! (c) 2009  Infineon Technologies AG, Munich
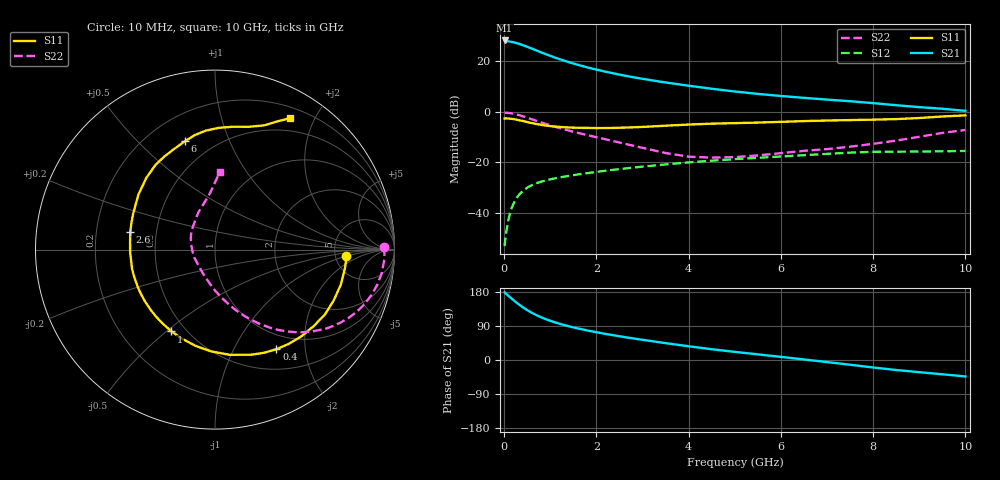
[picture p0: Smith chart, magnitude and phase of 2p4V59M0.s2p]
! Infineon Technologies  Discrete & RF Semiconductors
! BFP420
! VCE =  4.5 V,  IC =  9.0 mA
! Common Emitter S-Parameters:  Nov 2009
# GHz  S  MA  R  50
!  f  S11  S21  S12  S22
! GHz  MAG  ANG  MAG  ANG  MAG  ANG  MAG  ANG
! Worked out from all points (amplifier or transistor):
!   46 points, 10 MHz to 10 GHz, reference 50 ohm
!   highest |S21| = 28.1 dB at 10 MHz (marker M1)
!   |S21| within 3 dB of that: start of sweep to 569.1 MHz
!   unconditionally stable (mu >= 1): start of sweep to 19.03 MHz; 2.469 GHz to end of sweep
!   at 300 MHz: K = 0.27, MSG = 30.1 dB, |S12| = -33.4 dB
!   at 1.7 GHz: K = 0.79, MSG = 21.3 dB, |S12| = -24.6 dB
!   at 10 GHz: K = 1.09, MAG = 6.1 dB, |S12| = -15.6 dB
!   S11 on the Smith chart (normalised r, x): 10 MHz: 6.20, -0.97; 400 MHz: 0.77, -1.50; 1 GHz: 0.42, -0.52; 2.6 GHz: 0.35, +0.09; 6 GHz: 0.35, +0.70; 10 GHz: 0.33, +1.67
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0.01  0.7282 -2.9  25.32 178.7  0.0022 4.0  0.9401 0.8
0.02  0.7335 -2.9  24.62 177.2  0.0028 31.0  0.9441 -1.4
0.1  0.7278 -15.6  24.3 168.6  0.0079 66.0  0.9377 -8.2
0.2  0.7111 -30.6  23.36 158.2  0.0149 67.6  0.9077 -16.2
0.3  0.6819 -45.1  22.05 148.4  0.0214 64.1  0.8635 -23.5
0.4  0.6522 -58.4  20.55 139.6  0.0268 60.1  0.8116 -29.9
0.5  0.6203 -70.7  18.98 131.7  0.0314 56.5  0.7574 -35.6
0.6  0.5918 -82.1  17.47 124.6  0.0352 53.3  0.7052 -40.4
0.7  0.5672 -92.4  16.06 118.4  0.0384 50.7  0.656 -44.7
0.8  0.547 -101.5  14.75 112.9  0.0412 48.6  0.6116 -48.3
1  0.5163 -118.0  12.58 103.5  0.0459 45.5  0.5349 -54.6
1.3  0.4901 -137.8  10.11 92.3  0.0519 42.7  0.4464 -62.1
1.7  0.4755 -158.5  7.902 80.6  0.0591 40.4  0.3605 -70.6
2.2  0.473 -178.4  6.116 68.8  0.0679 38.1  0.2831 -80.1
2.6  0.4822 168.1  5.145 60.6  0.0749 36.0  0.2329 -88.9
3.5  0.5255 144.3  3.747 44.5  0.0904 31.0  0.1519 -115.0
4.5  0.5763 125.2  2.819 28.4  0.1072 24.2  0.1232 -157.8
5.5  0.6052 112.1  2.232 14.8  0.1221 17.4  0.1361 167.5
6  0.6262 105.6  2.029 8.2  0.1295 14.0  0.151 153.2
7  0.6649 94.4  1.723 -5.5  0.1461 6.1  0.1815 131.2
8.5  0.7096 74.6  1.332 -26.4  0.1616 -9.3  0.2667 103.0
10  0.841 60.4  1.032 -43.4  0.1669 -19.5  0.4331 86.4
